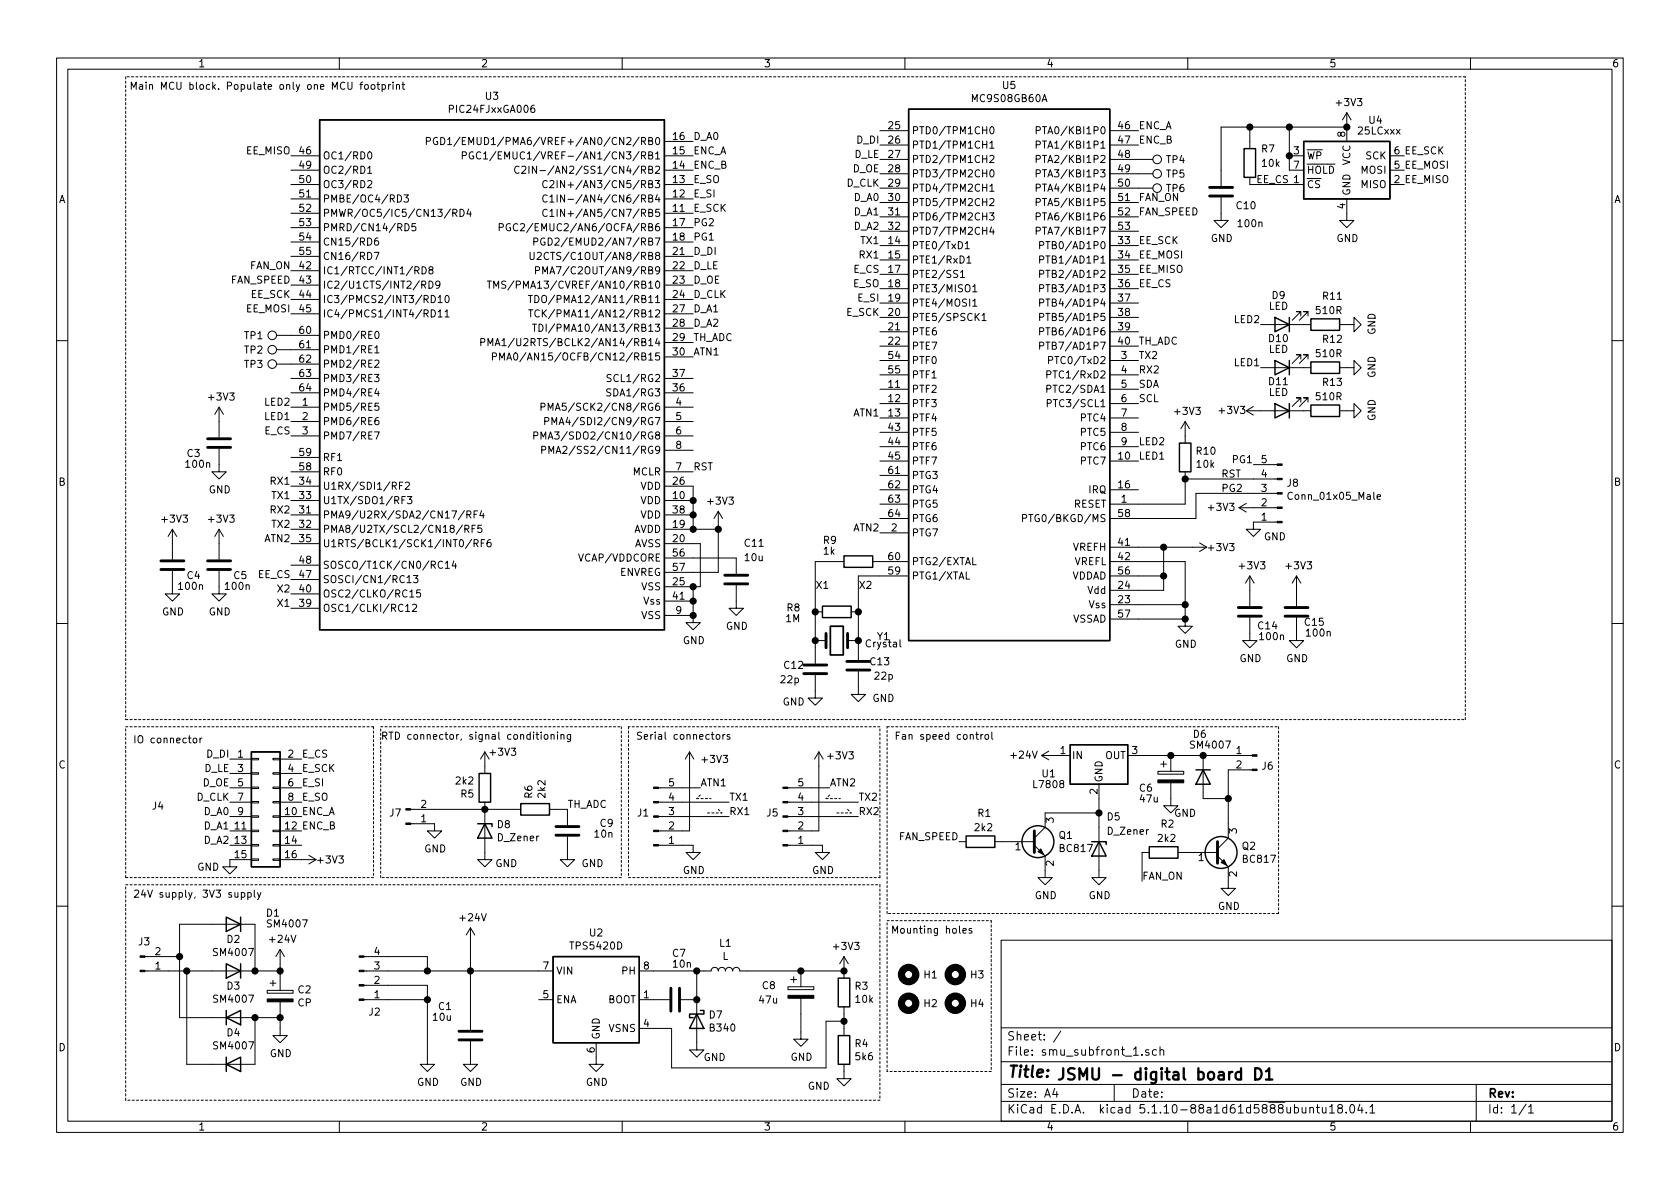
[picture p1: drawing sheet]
<svg xmlns="http://www.w3.org/2000/svg" width="297mm" height="210mm" viewBox="0 0 297 210" stroke-linecap="round" stroke-linejoin="round" font-family="sans-serif">
<defs><g id="words">
<g font-size="2.8">
<text x="178" y="190.5">Title:</text>
<text x="186.7" y="191">JSMU - digital board D1</text>
</g>
<g font-size="2.1">
<text x="178" y="184">Sheet: /</text>
<text x="178" y="186.7">File: smu_subfront_1.sch</text>
<text x="178" y="196.9">KiCad E.D.A. kicad 5.1.10-88a1d61d5888ubuntu18.04.1</text>
<text x="178" y="194.1">Size: A4</text>
<text x="200" y="194.1">Date:</text>
<text x="263" y="194.1">Rev:</text>
<text x="263" y="196.9">Id: 1/1</text>
</g>
<g font-size="1.8">
<text x="35" y="11.9">1</text>
<text x="85" y="11.9">2</text>
<text x="135" y="11.9">3</text>
<text x="185" y="11.9">4</text>
<text x="235" y="11.9">5</text>
<text x="285" y="11.9">6</text>
<text x="22.9" y="15.9">Main MCU block. Populate only one MCU footprint</text>
<text x="85.9" y="17.6">U3</text>
<text x="177.3" y="15.7">U5</text>
<text x="79.7" y="20">PIC24FJxxGA006</text>
<text x="157.1" y="22.9">25</text>
<text x="161.2" y="23.7">PTD0/TPM1CH0</text>
<text x="172.1" y="18.1">MC9S08GB60A</text>
<text x="184.5" y="23.7">PTA0/KBI1P0</text>
<text x="197.8" y="22.9">46</text>
<text x="201.3" y="22.9">ENC_A</text>
<text x="236.4" y="18.8">+3V3</text>
<text x="240.2" y="23.8">25LCxxx</text>
<text x="242.1" y="21.9">U4</text>
<text x="43.6" y="27.3">EE_MISO</text>
<text x="53" y="27.3">46</text>
<text x="53" y="29.8">49</text>
<text x="57" y="28.2">OC1/RD0</text>
<text x="81.7" y="25.6">PGD1/EMUD1/PMA6/VREF+/AN0/CN2/RB0</text>
<text x="87.6" y="28.2">PGC1/EMUC1/VREF-/AN1/CN3/RB1</text>
<text x="119" y="29.8">14</text>
<text x="119" y="27.3">15</text>
<text x="119" y="24.8">16</text>
<text x="122.6" y="29.8">ENC_B</text>
<text x="122.6" y="27.3">ENC_A</text>
<text x="122.6" y="24.8">D_A0</text>
<text x="151.1" y="27.9">D_LE</text>
<text x="151.5" y="25.4">D_DI</text>
<text x="157.1" y="25.4">26</text>
<text x="157.1" y="27.9">27</text>
<text x="161.2" y="26.3">PTD1/TPM1CH1</text>
<text x="161.2" y="28.8">PTD2/TPM1CH2</text>
<text x="184.5" y="26.3">PTA1/KBI1P1</text>
<text x="184.5" y="28.8">PTA2/KBI1P2</text>
<text x="197.8" y="25.4">47</text>
<text x="197.8" y="27.9">48</text>
<text x="201.3" y="25.4">ENC_B</text>
<text x="206.2" y="28.9">TP4</text>
<text x="223.1" y="27">R7</text>
<text x="223.2" y="29.5">10k</text>
<text x="228.8" y="27.3">3</text>
<text x="228.8" y="29.8">7</text>
<text x="231" y="28.2">WP</text>
<text x="237.9" y="24.2" transform="rotate(-90 237.9 24.2)">8</text>
<text x="238.8" y="29.3" transform="rotate(-90 238.8 29.3)">VCC</text>
<text x="241.5" y="28.2">SCK</text>
<text x="246.5" y="29.8">5 EE_MOSI</text>
<text x="246.5" y="27.3">6 EE_SCK</text>
<text x="10.4" y="35.9">A</text>
<text x="53" y="32.4">50</text>
<text x="53" y="34.9">51</text>
<text x="57" y="30.7">OC2/RD1</text>
<text x="57" y="33.3">OC3/RD2</text>
<text x="57" y="35.8">PMBE/OC4/RD3</text>
<text x="96.4" y="30.7">C2IN-/AN2/SS1/CN4/RB2</text>
<text x="99.8" y="33.3">C2IN+/AN3/CN5/RB3</text>
<text x="100.3" y="35.8">C1IN-/AN4/CN6/RB4</text>
<text x="119" y="34.9">12</text>
<text x="119" y="32.4">13</text>
<text x="122.6" y="32.4">E_SO</text>
<text x="122.6" y="34.9">E_SI</text>
<text x="149.7" y="33">D_CLK</text>
<text x="150.7" y="30.5">D_OE</text>
<text x="151.1" y="35.6">D_A0</text>
<text x="157.1" y="30.5">28</text>
<text x="157.1" y="33">29</text>
<text x="157.1" y="35.6">30</text>
<text x="161.2" y="31.4">PTD3/TPM2CH0</text>
<text x="161.2" y="33.9">PTD4/TPM2CH1</text>
<text x="184.5" y="31.4">PTA3/KBI1P3</text>
<text x="184.5" y="33.9">PTA4/KBI1P4</text>
<text x="197.8" y="30.5">49</text>
<text x="197.8" y="33">50</text>
<text x="197.8" y="35.6">51</text>
<text x="201.3" y="35.6">FAN_ON</text>
<text x="206.2" y="34">TP6</text>
<text x="206.2" y="31.4">TP5</text>
<text x="222.2" y="32.4">EE_CS 1</text>
<text x="231" y="33.3">CS</text>
<text x="231" y="30.7">HOLD</text>
<text x="238.8" y="34.7" transform="rotate(-90 238.8 34.7)">GND</text>
<text x="240.7" y="33.3">MISO</text>
<text x="240.7" y="30.7">MOSI</text>
<text x="246.5" y="32.4">2 EE_MISO</text>
<text x="285.4" y="35.9">A</text>
<text x="53" y="37.5">52</text>
<text x="53" y="40">53</text>
<text x="57" y="38.3">PMWR/OC5/IC5/CN13/RD4</text>
<text x="57" y="40.9">PMRD/CN14/RD5</text>
<text x="91.9" y="40.9">PGC2/EMUC2/AN6/OCFA/RB6</text>
<text x="99.8" y="38.3">C1IN+/AN5/CN7/RB5</text>
<text x="119" y="37.5">11</text>
<text x="119" y="40">17</text>
<text x="122.6" y="37.5">E_SCK</text>
<text x="122.6" y="40">PG2</text>
<text x="151.1" y="38.1">D_A1</text>
<text x="151.1" y="40.6">D_A2</text>
<text x="157.1" y="38.1">31</text>
<text x="157.1" y="40.6">32</text>
<text x="161.2" y="36.4">PTD5/TPM2CH2</text>
<text x="161.2" y="39">PTD6/TPM2CH3</text>
<text x="161.2" y="41.5">PTD7/TPM2CH4</text>
<text x="184.5" y="36.4">PTA5/KBI1P5</text>
<text x="184.5" y="39">PTA6/KBI1P6</text>
<text x="184.5" y="41.5">PTA7/KBI1P7</text>
<text x="197.8" y="38.1">52</text>
<text x="197.8" y="40.6">53</text>
<text x="201.3" y="38.1">FAN_SPEED</text>
<text x="218.7" y="37">C10</text>
<text x="219" y="40.2">100n</text>
<text x="237.9" y="36.9" transform="rotate(-90 237.9 36.9)">4</text>
<text x="44.2" y="47.6">FAN_ON</text>
<text x="53" y="47.6">42</text>
<text x="53" y="42.5">54</text>
<text x="53" y="45.1">55</text>
<text x="57" y="43.4">CN15/RD6</text>
<text x="57" y="46">CN16/RD7</text>
<text x="96.6" y="46">U2CTS/C1OUT/AN8/RB8</text>
<text x="97.4" y="43.4">PGD2/EMUD2/AN7/RB7</text>
<text x="119" y="42.5">18</text>
<text x="119" y="45.1">21</text>
<text x="119" y="47.6">22</text>
<text x="122.6" y="47.6">D_LE</text>
<text x="122.6" y="45.1">D_DI</text>
<text x="122.6" y="42.5">PG1</text>
<text x="152.1" y="45.7">RX1</text>
<text x="152.3" y="43.2">TX1</text>
<text x="157.1" y="43.2">14</text>
<text x="157.1" y="45.7">15</text>
<text x="161.2" y="44.1">PTE0/TxD1</text>
<text x="161.2" y="46.6">PTE1/RxD1</text>
<text x="185" y="44.1">PTB0/AD1P0</text>
<text x="185" y="46.6">PTB1/AD1P1</text>
<text x="197.8" y="43.2">33</text>
<text x="197.8" y="45.7">34</text>
<text x="201.3" y="43.2">EE_SCK</text>
<text x="201.3" y="45.7">EE_MOSI</text>
<text x="214.1" y="42.8">GND</text>
<text x="236.3" y="42.8">GND</text>
<text x="40.8" y="50.2">FAN_SPEED</text>
<text x="44.3" y="52.7">EE_SCK</text>
<text x="53" y="50.2">43</text>
<text x="53" y="52.7">44</text>
<text x="57" y="48.5">IC1/RTCC/INT1/RD8</text>
<text x="57" y="51">IC2/U1CTS/INT2/RD9</text>
<text x="57" y="53.6">IC3/PMCS2/INT3/RD10</text>
<text x="90.3" y="51">TMS/PMA13/CVREF/AN10/RB10</text>
<text x="96.8" y="53.6">TDO/PMA12/AN11/RB11</text>
<text x="97.5" y="48.5">PMA7/C2OUT/AN9/RB9</text>
<text x="119" y="50.2">23</text>
<text x="119" y="52.7">24</text>
<text x="122.6" y="52.7">D_CLK</text>
<text x="122.6" y="50.2">D_OE</text>
<text x="150.9" y="50.8">E_SO</text>
<text x="151" y="48.3">E_CS</text>
<text x="151.7" y="53.3">E_SI</text>
<text x="157.1" y="48.3">17</text>
<text x="157.1" y="50.8">18</text>
<text x="157.1" y="53.3">19</text>
<text x="161.2" y="49.1">PTE2/SS1</text>
<text x="161.2" y="51.7">PTE3/MISO1</text>
<text x="185" y="49.1">PTB2/AD1P2</text>
<text x="185" y="51.7">PTB3/AD1P3</text>
<text x="197.8" y="48.3">35</text>
<text x="197.8" y="50.8">36</text>
<text x="197.8" y="53.3">37</text>
<text x="201.3" y="48.3">EE_MISO</text>
<text x="201.3" y="50.8">EE_CS</text>
<text x="224.9" y="52.9">D9</text>
<text x="234" y="53">R11</text>
<text x="43.2" y="60">TP1</text>
<text x="43.6" y="55.2">EE_MOSI</text>
<text x="53" y="55.2">45</text>
<text x="53" y="59">60</text>
<text x="57" y="56.1">IC4/PMCS1/INT4/RD11</text>
<text x="57" y="59.9">PMD0/RE0</text>
<text x="96.9" y="56.1">TCK/PMA11/AN12/RB12</text>
<text x="97.7" y="58.7">TDI/PMA10/AN13/RB13</text>
<text x="119" y="55.2">27</text>
<text x="119" y="57.8">28</text>
<text x="122.6" y="57.8">D_A2</text>
<text x="122.6" y="55.2">D_A1</text>
<text x="149.7" y="55.9">E_SCK</text>
<text x="157.1" y="55.9">20</text>
<text x="157.1" y="58.4">21</text>
<text x="161.2" y="54.2">PTE4/MOSI1</text>
<text x="161.2" y="56.8">PTE5/SPSCK1</text>
<text x="161.2" y="59.3">PTE6</text>
<text x="185" y="54.2">PTB4/AD1P4</text>
<text x="185" y="56.8">PTB5/AD1P5</text>
<text x="185" y="59.3">PTB6/AD1P6</text>
<text x="197.8" y="55.9">38</text>
<text x="197.8" y="58.4">39</text>
<text x="218.4" y="57.1">LED2</text>
<text x="224.3" y="54.8">LED</text>
<text x="232.8" y="55.5">510R</text>
<text x="243.2" y="59.2" transform="rotate(-90 243.2 59.2)">GND</text>
<text x="43.2" y="62.5">TP2</text>
<text x="43.2" y="65.1">TP3</text>
<text x="53" y="61.6">61</text>
<text x="53" y="64.1">62</text>
<text x="57" y="62.5">PMD1/RE1</text>
<text x="57" y="65">PMD2/RE2</text>
<text x="89.4" y="61.2">PMA1/U2RTS/BCLK2/AN14/RB14</text>
<text x="91.5" y="63.7">PMA0/AN15/OCFB/CN12/RB15</text>
<text x="119" y="60.3">29</text>
<text x="119" y="62.9">30</text>
<text x="122.6" y="60.3">TH_ADC</text>
<text x="122.6" y="62.9">ATN1</text>
<text x="157.1" y="61">22</text>
<text x="157.1" y="63.5">54</text>
<text x="161.2" y="61.8">PTE7</text>
<text x="161.2" y="64.4">PTF0</text>
<text x="185" y="61.8">PTB7/AD1P7</text>
<text x="186.4" y="64.4">PTC0/TxD2</text>
<text x="197.8" y="61">40</text>
<text x="198.3" y="63.5">3</text>
<text x="201.3" y="63.5">TX2</text>
<text x="201.3" y="61">TH_ADC</text>
<text x="218.4" y="64.8">LED1</text>
<text x="224.3" y="62.4">LED</text>
<text x="224.4" y="60.5">D10</text>
<text x="232.8" y="63.2">510R</text>
<text x="234" y="60.6">R12</text>
<text x="37" y="70.8">+3V3</text>
<text x="46.9" y="71.7">LED2</text>
<text x="53" y="66.7">63</text>
<text x="53" y="69.2">64</text>
<text x="53.5" y="71.7">1</text>
<text x="57" y="67.6">PMD3/RE3</text>
<text x="57" y="70.1">PMD4/RE4</text>
<text x="108.1" y="70.1">SDA1/RG3</text>
<text x="108.3" y="67.6">SCL1/RG2</text>
<text x="119" y="69.2">36</text>
<text x="119" y="66.7">37</text>
<text x="119.5" y="71.7">4</text>
<text x="157.1" y="68.6">11</text>
<text x="157.1" y="71.1">12</text>
<text x="157.1" y="66">55</text>
<text x="161.2" y="69.5">PTF2</text>
<text x="161.2" y="66.9">PTF1</text>
<text x="186" y="69.5">PTC2/SDA1</text>
<text x="186.2" y="66.9">PTC1/RxD2</text>
<text x="198.3" y="66">4</text>
<text x="198.3" y="68.6">5</text>
<text x="198.3" y="71.1">6</text>
<text x="201.3" y="71.1">SCL</text>
<text x="201.3" y="68.6">SDA</text>
<text x="201.3" y="66">RX2</text>
<text x="224.3" y="70">LED</text>
<text x="224.4" y="68.1">D11</text>
<text x="232.8" y="70.8">510R</text>
<text x="234" y="68.2">R13</text>
<text x="243.2" y="66.8" transform="rotate(-90 243.2 66.8)">GND</text>
<text x="46.8" y="76.8">E_CS</text>
<text x="46.9" y="74.3">LED1</text>
<text x="53.5" y="74.3">2</text>
<text x="53.5" y="76.8">3</text>
<text x="57" y="72.6">PMD5/RE5</text>
<text x="57" y="75.2">PMD6/RE6</text>
<text x="57" y="77.7">PMD7/RE7</text>
<text x="97.6" y="77.7">PMA3/SDO2/CN10/RG8</text>
<text x="98.7" y="72.6">PMA5/SCK2/CN8/RG6</text>
<text x="99.5" y="75.2">PMA4/SDI2/CN9/RG7</text>
<text x="119.5" y="74.3">5</text>
<text x="119.5" y="76.8">6</text>
<text x="151" y="73.7">ATN1</text>
<text x="157.1" y="73.7">13</text>
<text x="157.1" y="76.2">43</text>
<text x="161.2" y="72">PTF3</text>
<text x="161.2" y="74.5">PTF4</text>
<text x="161.2" y="77.1">PTF5</text>
<text x="186.2" y="72">PTC3/SCL1</text>
<text x="191.2" y="74.5">PTC4</text>
<text x="191.2" y="77.1">PTC5</text>
<text x="198.3" y="73.7">7</text>
<text x="198.3" y="76.2">8</text>
<text x="207.8" y="73.4">+3V3</text>
<text x="215.7" y="73.2">+3V3</text>
<text x="243.2" y="74.5" transform="rotate(-90 243.2 74.5)">GND</text>
<text x="33" y="82.7">100n</text>
<text x="33.1" y="80.8">C3</text>
<text x="53" y="83.2">58</text>
<text x="53" y="80.6">59</text>
<text x="57" y="81.5">RF1</text>
<text x="99.1" y="80.3">PMA2/SS2/CN11/RG9</text>
<text x="119.5" y="83.2">7</text>
<text x="119.5" y="79.4">8</text>
<text x="122.6" y="83.2">RST</text>
<text x="157.1" y="78.7">44</text>
<text x="157.1" y="81.3">45</text>
<text x="157.1" y="83.8">61</text>
<text x="161.2" y="79.6">PTF6</text>
<text x="161.2" y="82.2">PTF7</text>
<text x="191.2" y="82.2">PTC7</text>
<text x="191.2" y="79.6">PTC6</text>
<text x="197.8" y="81.3">10</text>
<text x="198.3" y="78.7">9</text>
<text x="201.3" y="78.7">LED2</text>
<text x="201.3" y="81.3">LED1</text>
<text x="211.6" y="80.4">R10</text>
<text x="211.7" y="82.7">10k</text>
<text x="218.1" y="81.9">PG1</text>
<text x="223" y="81.9">5</text>
<text x="10.4" y="85.9">B</text>
<text x="36.9" y="87.2">GND</text>
<text x="48" y="85.7">RX1</text>
<text x="48.2" y="88.3">TX1</text>
<text x="53" y="88.3">33</text>
<text x="53" y="85.7">34</text>
<text x="57" y="89.1">U1TX/SDO1/RF3</text>
<text x="57" y="86.6">U1RX/SDI1/RF2</text>
<text x="57" y="84.1">RF0</text>
<text x="111.9" y="84.1">MCLR</text>
<text x="113.2" y="89.1">VDD</text>
<text x="113.2" y="86.6">VDD</text>
<text x="119" y="88.3">10</text>
<text x="119" y="85.7">26</text>
<text x="125.3" y="89.2">+3V3</text>
<text x="157.1" y="86.4">62</text>
<text x="157.1" y="88.9">63</text>
<text x="161.2" y="84.7">PTG3</text>
<text x="161.2" y="87.2">PTG4</text>
<text x="161.2" y="89.8">PTG5</text>
<text x="189.8" y="89.8">RESET</text>
<text x="192.6" y="87.2">IRQ</text>
<text x="197.8" y="86.4">16</text>
<text x="198.3" y="88.9">1</text>
<text x="215.9" y="84.4">RST</text>
<text x="215.9" y="87">PG2</text>
<text x="223" y="89.5">2</text>
<text x="223" y="87">3</text>
<text x="223" y="84.4">4</text>
<text x="227.6" y="86.1">J8</text>
<text x="228.2" y="88.4">Conn_01x05_Male</text>
<text x="285.4" y="85.9">B</text>
<text x="28.8" y="92.4">+3V3</text>
<text x="37" y="92.4">+3V3</text>
<text x="46.8" y="95.9">ATN2</text>
<text x="48" y="90.8">RX2</text>
<text x="48.2" y="93.3">TX2</text>
<text x="53" y="90.8">31</text>
<text x="53" y="93.3">32</text>
<text x="53" y="95.9">35</text>
<text x="57" y="91.7">PMA9/U2RX/SDA2/CN17/RF4</text>
<text x="57" y="94.2">PMA8/U2TX/SCL2/CN18/RF5</text>
<text x="112" y="94.2">AVDD</text>
<text x="113.2" y="91.7">VDD</text>
<text x="119" y="93.3">19</text>
<text x="119" y="95.9">20</text>
<text x="119" y="90.8">38</text>
<text x="151" y="94">ATN2</text>
<text x="157.1" y="91.4">64</text>
<text x="157.6" y="94">2</text>
<text x="161.2" y="94.9">PTG7</text>
<text x="161.2" y="92.3">PTG6</text>
<text x="182.2" y="92.3">PTG0/BKGD/MS</text>
<text x="197.8" y="91.4">58</text>
<text x="213.8" y="90.3">+3V3</text>
<text x="223" y="92.1">1</text>
<text x="223.5" y="95.5">GND</text>
<text x="53" y="99.7">48</text>
<text x="57" y="96.8">U1RTS/BCLK1/SCK1/INT0/RF6</text>
<text x="57" y="100.6">SOSCO/T1CK/CN0/RC14</text>
<text x="102.7" y="99.3">VCAP/VDDCORE</text>
<text x="109.5" y="101.8">ENVREG</text>
<text x="112.1" y="96.8">AVSS</text>
<text x="119" y="98.4">56</text>
<text x="119" y="101">57</text>
<text x="131.7" y="96.7">C11</text>
<text x="131.8" y="99.2">10u</text>
<text x="145.6" y="96.2">R9</text>
<text x="145.6" y="98.1">1k</text>
<text x="157.1" y="101.6">59</text>
<text x="157.1" y="99.1">60</text>
<text x="161.2" y="99.9">PTG2/EXTAL</text>
<text x="189.7" y="97.4">VREFH</text>
<text x="189.9" y="99.9">VREFL</text>
<text x="197.8" y="96.5">41</text>
<text x="197.8" y="99.1">42</text>
<text x="197.8" y="101.6">56</text>
<text x="213.8" y="97.5">+3V3</text>
<text x="219.3" y="100.7">+3V3</text>
<text x="227.5" y="100.7">+3V3</text>
<text x="31.7" y="104.3">100n</text>
<text x="33.1" y="102.4">C4</text>
<text x="40" y="104.3">100n</text>
<text x="41.4" y="102.4">C5</text>
<text x="45.6" y="102.2">EE_CS</text>
<text x="49.3" y="107.3">X1</text>
<text x="49.3" y="104.8">X2</text>
<text x="53" y="107.3">39</text>
<text x="53" y="104.8">40</text>
<text x="53" y="102.2">47</text>
<text x="57" y="105.7">OSC2/CLKO/RC15</text>
<text x="57" y="103.1">SOSCI/CN1/RC13</text>
<text x="113.4" y="104.4">VSS</text>
<text x="113.8" y="106.9">Vss</text>
<text x="119" y="103.5">25</text>
<text x="119" y="106">41</text>
<text x="144.1" y="104.1">X1</text>
<text x="151.8" y="104.1">X2</text>
<text x="161.2" y="102.5">PTG1/XTAL</text>
<text x="189.4" y="102.5">VDDAD</text>
<text x="192.4" y="105">Vdd</text>
<text x="192.6" y="107.6">Vss</text>
<text x="197.8" y="106.7">23</text>
<text x="197.8" y="104.1">24</text>
<text x="28.7" y="108.8">GND</text>
<text x="36.9" y="108.8">GND</text>
<text x="57" y="108.2">OSC1/CLKI/RC12</text>
<text x="113.4" y="109.5">VSS</text>
<text x="119.5" y="108.6">9</text>
<text x="120.7" y="113.9">GND</text>
<text x="128.3" y="111.4">GND</text>
<text x="139" y="110">1M</text>
<text x="139.2" y="108.1">R8</text>
<text x="155.1" y="113.2">Y1</text>
<text x="189.6" y="110.1">VSSAD</text>
<text x="197.8" y="109.2">57</text>
<text x="222.5" y="111.3">C14</text>
<text x="222.9" y="113.2">100n</text>
<text x="230.8" y="110.7">C15</text>
<text x="231.1" y="112.6">100n</text>
<text x="138.7" y="118.3">C12</text>
<text x="153.2" y="114.5">Crystal</text>
<text x="153.9" y="117.6">C13</text>
<text x="207.7" y="114.5">GND</text>
<text x="219.2" y="117.1">GND</text>
<text x="227.4" y="117.1">GND</text>
<text x="138.1" y="120.8">22p</text>
<text x="138.4" y="124.8">GND</text>
<text x="154.3" y="124.1">GND</text>
<text x="154.7" y="120.2">22p</text>
<text x="23.5" y="131.4">IO connector</text>
<text x="67.3" y="130.8">RTD connector, signal conditioning</text>
<text x="112.4" y="130.8">Serial connectors</text>
<text x="158.1" y="130.8">Fan speed control</text>
<text x="211" y="130.5">D6</text>
<text x="10.4" y="135.9">C</text>
<text x="36.1" y="136.5">D_LE</text>
<text x="36.6" y="134">D_DI</text>
<text x="42.1" y="134">1</text>
<text x="42.1" y="136.5">3</text>
<text x="51" y="134">2</text>
<text x="51" y="136.5">4</text>
<text x="53.3" y="134">E_CS</text>
<text x="53.3" y="136.5">E_SCK</text>
<text x="86.8" y="133.6">+3V3</text>
<text x="124.3" y="134.9">+3V3</text>
<text x="146.5" y="134.3">+3V3</text>
<text x="178.9" y="134.2">+24V</text>
<text x="184.3" y="137.5">U1</text>
<text x="187.5" y="133.3">1</text>
<text x="189.5" y="134.2">IN</text>
<text x="195.4" y="134.2">OUT</text>
<text x="200.2" y="133.3">3</text>
<text x="210.7" y="132.4">SM4007</text>
<text x="218.6" y="133.3">1</text>
<text x="218.6" y="135.9">2</text>
<text x="223.2" y="136.1">J6</text>
<text x="285.4" y="135.9">C</text>
<text x="27" y="143.2">J4</text>
<text x="34.7" y="141.6">D_CLK</text>
<text x="35.8" y="139.1">D_OE</text>
<text x="42.1" y="139.1">5</text>
<text x="42.1" y="141.6">7</text>
<text x="51" y="139.1">6</text>
<text x="51" y="141.6">8</text>
<text x="53.3" y="139.1">E_SI</text>
<text x="53.3" y="141.6">E_SO</text>
<text x="74.4" y="142.9">2</text>
<text x="80.7" y="138.7">2k2</text>
<text x="81.5" y="141">R5</text>
<text x="94.1" y="141.1" transform="rotate(-90 94.1 141.1)">R6</text>
<text x="96.4" y="141" transform="rotate(-90 96.4 141)">2k2</text>
<text x="100.3" y="142.9">TH_ADC</text>
<text x="118.3" y="141.6">4</text>
<text x="118.3" y="139.1">5</text>
<text x="123.8" y="139.1">ATN1</text>
<text x="128.9" y="141.6">TX1</text>
<text x="141.1" y="141.6">4</text>
<text x="141.1" y="139.1">5</text>
<text x="146.7" y="139.1">ATN2</text>
<text x="151.8" y="141.6">TX2</text>
<text x="182.9" y="139.4">L7808</text>
<text x="194.1" y="140.4" transform="rotate(-90 194.1 140.4)">2</text>
<text x="194.9" y="138.4" transform="rotate(-90 194.9 138.4)">GND</text>
<text x="201.5" y="140">C6</text>
<text x="201.6" y="141.9">47u</text>
<text x="36.1" y="144.1">D_A0</text>
<text x="36.1" y="146.7">D_A1</text>
<text x="36.1" y="149.2">D_A2</text>
<text x="41.6" y="146.7">11</text>
<text x="41.6" y="149.2">13</text>
<text x="42.1" y="144.1">9</text>
<text x="50.5" y="144.1">10 ENC_A</text>
<text x="50.5" y="146.7">12 ENC_B</text>
<text x="50.5" y="149.2">14</text>
<text x="68.9" y="144.4">J7</text>
<text x="74.4" y="145.4">1</text>
<text x="88" y="146.5">D8</text>
<text x="88.1" y="148.8">D_Zener</text>
<text x="105.2" y="148.1">10n</text>
<text x="106.1" y="146.2">C9</text>
<text x="112.8" y="144.4">J1</text>
<text x="118.3" y="149.2">1</text>
<text x="118.3" y="146.7">2</text>
<text x="118.3" y="144.1">3</text>
<text x="128.9" y="144.1">RX1</text>
<text x="135.6" y="144.4">J5</text>
<text x="141.1" y="149.2">1</text>
<text x="141.1" y="146.7">2</text>
<text x="141.1" y="144.1">3</text>
<text x="151.8" y="144.1">RX2</text>
<text x="158.9" y="148.6">FAN_SPEED</text>
<text x="172.4" y="147">2k2</text>
<text x="172.9" y="144.4">R1</text>
<text x="186.3" y="145.5" transform="rotate(-90 186.3 145.5)">3</text>
<text x="187.3" y="148.4">Q1</text>
<text x="195.8" y="145.1">D5</text>
<text x="195.9" y="147.6">D_Zener</text>
<text x="204.8" y="148.9">2k2</text>
<text x="205.3" y="146.3">R2</text>
<text x="207.6" y="144.4">GND</text>
<text x="218.7" y="147.4" transform="rotate(-90 218.7 147.4)">3</text>
<text x="34.9" y="154">GND</text>
<text x="41.6" y="151.8">15</text>
<text x="50.5" y="151.8">16</text>
<text x="56.3" y="152.7">+3V3</text>
<text x="75" y="150.7">GND</text>
<text x="87.6" y="153.3">GND</text>
<text x="102.8" y="153.3">GND</text>
<text x="120.7" y="154.6">GND</text>
<text x="143.6" y="154.6">GND</text>
<text x="179.5" y="150.4">1</text>
<text x="186.3" y="153.1" transform="rotate(-90 186.3 153.1)">2</text>
<text x="187.5" y="150.7">BC817</text>
<text x="201.9" y="155.6">FAN_ON</text>
<text x="211.9" y="152.3">1</text>
<text x="218.7" y="155" transform="rotate(-90 218.7 155)">2</text>
<text x="219.7" y="150.3">Q2</text>
<text x="219.9" y="152.6">BC817</text>
<text x="23.5" y="158.7">24V supply, 3V3 supply</text>
<text x="183" y="159">GND</text>
<text x="192.5" y="159">GND</text>
<text x="215.3" y="160.9">GND</text>
<text x="24.5" y="167.2">J3</text>
<text x="40.2" y="166.7">D2</text>
<text x="47.1" y="162.1">D1</text>
<text x="47.5" y="164">SM4007</text>
<text x="47.8" y="166.7">+24V</text>
<text x="81.5" y="162.9">+24V</text>
<text x="101.1" y="167.9">TPS5420D</text>
<text x="104.3" y="165.6">U2</text>
<text x="127.3" y="167.4">L1</text>
<text x="147.5" y="168">+3V3</text>
<text x="157.5" y="165.1">Mounting holes</text>
<text x="27.5" y="171.4">1</text>
<text x="27.5" y="168.9">2</text>
<text x="38" y="169.1">SM4007</text>
<text x="66.2" y="174">2</text>
<text x="66.2" y="171.4">3</text>
<text x="66.2" y="168.9">4</text>
<text x="96" y="171.4">7</text>
<text x="98.3" y="172.3">VIN</text>
<text x="110.1" y="172.3">PH</text>
<text x="113.8" y="171.4">8</text>
<text x="118.9" y="169.2">C7</text>
<text x="119.1" y="171.1">10n</text>
<text x="127.7" y="169.7">L</text>
<text x="163.4" y="173">H1</text>
<text x="171.7" y="173">H3</text>
<text x="38" y="177.3">SM4007</text>
<text x="40.2" y="175">D3</text>
<text x="52.7" y="178">CP</text>
<text x="52.7" y="175.7">C2</text>
<text x="65.3" y="179.6">J2</text>
<text x="66.2" y="176.5">1</text>
<text x="77.6" y="178.6">C1</text>
<text x="96" y="176.5">5</text>
<text x="98.3" y="177.4">ENA</text>
<text x="107.4" y="177.4">BOOT</text>
<text x="113.8" y="176.5">1</text>
<text x="134.3" y="177.5">47u</text>
<text x="134.8" y="174.9">C8</text>
<text x="151.2" y="175">R3</text>
<text x="151.3" y="177.3">10k</text>
<text x="163.4" y="178.1">H2</text>
<text x="171.7" y="178.1">H4</text>
<text x="10.4" y="185.9">D</text>
<text x="38" y="185.6">SM4007</text>
<text x="40.2" y="183.3">D4</text>
<text x="76.6" y="180.5">10u</text>
<text x="106" y="183.9" transform="rotate(-90 106 183.9)">GND</text>
<text x="107.7" y="182.5">VSNS</text>
<text x="113.8" y="181.6">4</text>
<text x="125.4" y="180.1">D7</text>
<text x="125.6" y="182.4">B340</text>
<text x="151.2" y="185.2">R4</text>
<text x="285.4" y="185.9">D</text>
<text x="47.7" y="186.9">GND</text>
<text x="105.2" y="186.2" transform="rotate(-90 105.2 186.2)">6</text>
<text x="124.4" y="187.6">GND</text>
<text x="139.8" y="187.6">GND</text>
<text x="151.3" y="187.5">5k6</text>
<text x="73.7" y="192">GND</text>
<text x="81.4" y="192">GND</text>
<text x="103.6" y="192">GND</text>
<text x="142.8" y="192.7">GND</text>
<text x="35" y="199.9">1</text>
<text x="85" y="199.9">2</text>
<text x="135" y="199.9">3</text>
<text x="185" y="199.9">4</text>
<text x="235" y="199.9">5</text>
<text x="285" y="199.9">6</text>
</g>
</g></defs>
<g fill="none" stroke="#000" stroke-width=".18">
<path d="M10 10.3h277v189.9h-277zM12 12.2h273v186.1h-273zM60 10.3v1.9M63.6 15h.5M64.1 14.5l-.3 .2v1.1M64.6 15h.3l.2 .1-.1 .6-.3 .1-.2-.2zM65.7 15h.3l.3 .2-.1 .5-.3 .1-.3-.2zM66.6 15h.5M66.8 14.5v1.1l.3 .2M67.6 15h.3l.2 .2-.1 .5h-.4M67.6 15v1.2M68.7 15v.8"/>
<path d="M69.1 15l-.4 .2M69.5 14.5v.2M69.5 15v.8M70.1 15.1l.2-.1h.3v.8M70.1 15v.8M71.1 15h.5M71.2 14.5v1.1l.4 .2M94.5 18.6l-.4 .1a.87 .87 0 0 0 0 1.2l.4-.1v-.6l-.4-.1-.2 .2M110 10.3v1.9M160 10.3v1.9M210 10.3v1.9M238.1 19.9v5.1"/>
<path d="M238.1 19.9l-.7 1.3M238.1 19.9l.8 1.3M260 10.3v1.9M51.4 32.6h5.1M51.4 27.6h5.1M51.4 30.1h5.1M51.4 37.7h5.1M51.4 35.2h5.1M65 29.7l.4-.3v1.3M65 32l.5-.1 .2 .1v.3v.2l-.8 .7h.8M65 30.7h.7M65.1 27l.2-.2a.67 .67 0 0 1 .5 .7 .67 .67 0 0 1-.5 .6l-.3-.5z"/>
<path d="M70.3 34.5a.64 .64 0 0 1 .7 .6 .64 .64 0 0 1-.7 .6zM71.4 34.5h.8l-.4 .4 .3 .2 .1 .4-.2 .2-.6-.1M71.6 39.5a.64 .64 0 0 1 .7 .7 .64 .64 0 0 1-.7 .6zM73.5 39.5h-.6l-.1 .7 .2-.2 .5 .2v.5l-.2 .1-.5-.1M75.4 25l.6-.1 .1-.2-.1-.3-.1-.1h-.5v1.3M77.3 24.4a.59 .59 0 0 0-.7 .5 .59 .59 0 0 0 .7 .6l.1-.5h-.3M77.9 24.3a.64 .64 0 0 1 .8 .6 .64 .64 0 0 1-.8 .7zM79.1 24.7l.4-.4v1.3M79.1 25.6h.8M79.7 37l-1.1 1.6M80.1 37.7l.6-.1 .1-.2-.1-.3-.2-.1h-.4v1.3M80.4 37.7l.4 .6"/>
<path d="M81.3 37a.64 .64 0 0 1 .8 .6 .64 .64 0 0 1-.8 .7zM81.3 24.3l-1.1 1.6M81.7 27.5h.6l.2-.2-.1-.3-.2-.2h-.5v1.3M82.9 37l-.4 .8h.8M83.2 37.4v.9M83.7 26.9a.59 .59 0 0 0-.8 .6 .59 .59 0 0 0 .8 .6v-.5h-.2M85 27a.6 .6 0 0 0-.8 .4 .6 .6 0 0 0 .6 .7l.2-.1M85.5 27.2l.4-.4v1.3M85.5 28.1h.7M87.7 26.8l-1.1 1.6M90.2 39.6a.59 .59 0 0 0-.7 .6 .59 .59 0 0 0 .7 .6l.1-.5h-.3M91.5 39.7a.6 .6 0 0 0-.8 .4 .6 .6 0 0 0 .6 .7l.2-.1"/>
<path d="M91.8 29.5a.6 .6 0 0 0-.9 .4 .6 .6 0 0 0 .6 .8l.3-.2M92.3 29.5l.5-.1 .2 .3-.1 .2-.7 .8h.8M93.5 29.4v1.3M94.9 29.4v1.3l-.8-1.3v1.3M95.5 30.2h.9M96.7 37.1a.51 .51 0 0 0-.6 0 .51 .51 0 0 0-.1 .6 .46 .46 0 0 0 .2 .5 .46 .46 0 0 0 .5-.1M96.7 34.6a.51 .51 0 0 0-.6 0 .51 .51 0 0 0-.1 .6 .46 .46 0 0 0 .2 .5 .46 .46 0 0 0 .5-.1M96.7 32a.51 .51 0 0 0-.6 0 .51 .51 0 0 0-.1 .7 .46 .46 0 0 0 .2 .5 .46 .46 0 0 0 .5-.1M97.2 37.4l.4-.4v1.3M97.2 34.8l.4-.3v1.2M97.2 32l.5-.1 .2 .4v.2l-.7 .7h.7M97.2 38.3h.7"/>
<path d="M97.2 35.7h.7M98.5 31.9v1.3M98.5 34.5v1.2M98.5 37v1.3M99.8 37v1.3l-.7-1.3v1.3M99.8 34.5v1.2l-.7-1.2v1.2M99.8 31.9v1.3l-.7-1.3v1.3M117.5 32.6h5.1M117.5 27.6h5.1M117.5 30.1h5.1M117.5 37.7h5.1M117.5 35.2h5.1"/>
<path d="M117.5 25h5.1M155.6 33.3h5.1M155.6 30.7h5.1M155.6 28.2h5.1M155.6 23.1h5.1M155.6 25.6h5.1M155.6 35.8h5.1M155.6 38.3h5.1M175 37.6h.7l-.4 .5 .4 .1v.6l-.2 .1-.5-.1M175 25.3l.4-.4v1.3M175 27.6l.5-.1 .2 .1v.2v.2l-.7 .7h.7M175 32.9l.4-.3v1.2"/>
<path d="M175 35.2l.5-.1 .2 .1v.3v.2l-.7 .7h.7M175 26.2h.7M175 33.8h.7M175.1 22.5l.2-.1a.67 .67 0 0 1 .5 .6 .67 .67 0 0 1-.5 .7l-.3-.5zM175.1 30.1l.2-.1a.67 .67 0 0 1 .5 .7 .67 .67 0 0 1-.5 .6l-.3-.5zM183.2 23.1l.7-.1v-.5l-.7-.1v1.3M183.2 25.6l.7-.1v-.4l-.7-.2v1.3M183.2 28.1l.7-.1v-.4l-.7-.1v1.2M183.2 30.7l.7-.1v-.5l-.7-.1v1.3M183.2 33.2l.7-.1v-.4l-.7-.1v1.2M183.2 35.8l.7-.1v-.5l-.7-.1v1.3M183.2 38.3l.7-.1v-.4l-.7-.2v1.3"/>
<path d="M196.2 33.3h7.6M196.2 30.7h7.6M196.2 28.2h7.6M196.2 23.1h5.1M196.2 25.6h5.1M196.2 35.8h5.1M196.2 38.3h5.1M215.9 34.9v4.1h1.3l-1.3 1.3-1.3-1.3h1.3M221 22.5v3.8M221 31.4v1.2h9.5M228 27.6h2.5M228 22.5v7.6h2.5"/>
<path d="M238.1 35.2v3.8h1.3l-1.3 1.3-1.2-1.3h1.2M238.1 22.5h-22.2v10.4M245.7 32.6h2.6M245.7 27.6h2.6M245.7 30.1h2.6M48.9 59.3h7.6M51.4 40.3h5.1M51.4 42.8h5.1M51.4 45.3h5.1M51.4 47.9h5.1M51.4 50.4h5.1M51.4 53h5.1"/>
<path d="M51.4 55.5h5.1M66.2 44.6h.8l-.5 1.3M66.4 58.7l.2-.1a.67 .67 0 0 1 .4 .6 .67 .67 0 0 1-.4 .7l-.3-.5zM66.8 42.1l-.4 .1-.2 .4 .1 .6 .2 .2 .3-.1 .2-.2-.2-.5h-.3l-.3 .2M73.4 47.8h.6l.1-.2-.1-.3-.2-.1h-.4v1.2M73.7 47.8l.4 .6M74.6 50.4l.6-.1v-.5l-.1-.1h-.5v1.3M74.6 47.2a.64 .64 0 0 1 .8 .6 .64 .64 0 0 1-.8 .6zM74.9 50.4l.4 .6M75.8 49.7a.64 .64 0 0 1 .8 .6 .64 .64 0 0 1-.8 .7zM76.1 47.7l-.2-.1v-.3l.4-.1 .2 .1v.3l-.6 .2-.1 .1v.3l.3 .2h.2l.3-.2-.1-.4-.2-.1M76.3 52.2a.64 .64 0 0 1 .7 .7 .64 .64 0 0 1-.7 .6z"/>
<path d="M76.3 54.8a.64 .64 0 0 1 .7 .6 .64 .64 0 0 1-.7 .7zM77.5 52.6l.3-.4v1.3M77.5 55.1l.3-.3v1.3M77.5 53.5h.7M77.5 56.1h.7M77.8 50.3l-.3 .2-.3-.1-.2-.1 .2-.5 .3-.1 .2 .1a.87 .87 0 0 1-.3 1.2h-.2M78.7 55.1l.3-.3v1.3M78.7 56.1h.7M78.8 52.4l.2-.2a.67 .67 0 0 1 .4 .7 .67 .67 0 0 1-.4 .6l-.2-.1-.1-.4zM86.2 49.7h.7M86.5 49.7v1.3M87.3 51v-1.3l.4 .9 .5-.9v1.3"/>
<path d="M88.3 40.2l.7-.1v-.4l-.7-.2v1.3M89.4 49.8l-.4-.1-.3 .1v.4l.6 .2 .1 .3-.2 .3-.5-.1M93.4 52.2h.7M93.5 54.8h.7M93.7 44.6v1.1l.3 .2h.2l.2-.2v-1.1M93.8 52.2v1.3M93.8 54.8v1.3M94.1 57.3h.8M94.4 42.7h.6v-.5l-.1-.1h-.5v1.3M94.5 57.3v1.3M94.6 52.2a.64 .64 0 0 1 .7 .7 .64 .64 0 0 1-.7 .6zM94.7 47.8h.6l.1-.5-.2-.1h-.5v1.2"/>
<path d="M95 44.7l.5-.1 .2 .4v.2l-.8 .7h.8M95.3 57.3a.64 .64 0 0 1 .7 .7 .64 .64 0 0 1-.7 .6zM95.4 54.9a.6 .6 0 0 0-.9 .4 .6 .6 0 0 0 .6 .8l.3-.2M95.8 52.4l.2-.1a.42 .42 0 0 1 .6 .1 .88 .88 0 0 1-.3 1.1h-.3a1.07 1.07 0 0 1-.2-1.1zM95.9 54.8v1.3M96 48.4v-1.2l.4 .9 .4-.9v1.2M96.1 55.3l.5 .8M96.3 42.2a.59 .59 0 0 0-.7 .5 .59 .59 0 0 0 .7 .6l.1-.5h-.3M96.6 57.3v1.3M96.6 54.8l-.7 .7M96.9 42.1a.64 .64 0 0 1 .7 .6 .64 .64 0 0 1-.7 .7zM98.1 57.3l-1.1 1.6"/>
<path d="M117.5 40.3h5.1M117.5 42.8h5.1M117.5 45.3h5.1M117.5 47.9h5.1M117.5 50.4h5.1M117.5 53h5.1M117.5 55.5h5.1M117.5 58h5.1M155.6 43.4h5.1M155.6 46h5.1M155.6 48.5h5.1M155.6 51h5.1"/>
<path d="M155.6 53.6h5.1M155.6 56.1h5.1M155.6 58.7h5.1M155.6 40.9h5.1M169.8 48.2l.4-.4v1.3M169.8 49.1h.7M170.7 43.1l.3-.4v1.3M170.7 44h.7M171 45.6l.3-.3v1.2M171 46.5h.7M172 50.7l.4-.4v1.3M172 53.2l.4-.3v1.2"/>
<path d="M172 51.6h.7M172 54.1h.7M173.6 55.8l.4-.4v1.3M173.6 56.7h.7M175.3 40.1l-.3 .9h.8M175.6 40.6v.8M183.2 40.8l.7-.1v-.4l-.7-.1v1.2M183.8 43.4l.6-.1 .2-.2-.1-.3-.2-.1h-.5v1.3M183.8 45.9h.6l.2-.2-.1-.3-.2-.1h-.5v1.2M183.8 48.5l.6-.1 .2-.2-.1-.3-.2-.1h-.5v1.3M183.8 51l.6-.1 .2-.1-.1-.3-.2-.2h-.5v1.3M183.8 53.5h.6l.2-.2-.1-.3-.2-.1h-.5v1.2"/>
<path d="M183.8 56.1l.6-.1 .2-.2-.1-.3-.2-.1h-.5v1.3M183.8 58.6h.6l.2-.2-.1-.3-.2-.1h-.5v1.2M196.2 43.4h5.1M196.2 46h5.1M196.2 48.5h5.1M196.2 51h5.1M196.2 53.6h5.1M196.2 56.1h5.1M196.2 58.7h5.1M196.2 40.9h5.1M222.9 57.4h8.9M230 55.9v-.8h-.8h.8l-1.5 1.5"/>
<path d="M231.3 55.9v-.8h-.8h.8l-1.6 1.5M236.9 57.4h2.5v-1.3l1.3 1.3-1.3 1.3v-1.3M10 60.2h2M38.7 79.4v4h1.3l-1.3 1.3-1.2-1.3h1.2M38.7 72v5.3M38.7 72l-.7 1.3M38.7 72l.8 1.3M48.9 61.8h7.6M48.9 64.4h7.6M51.4 72h5.1M51.4 74.5h5.1M51.4 77.1h5.1"/>
<path d="M51.4 69.5h5.1M51.4 66.9h5.1M66.2 76.4h.9l-.6 1.2M66.2 66.2h.8l-.4 .5 .4 .1v.6l-.2 .1-.6-.1M66.3 61.5l.3-.4v1.3M66.3 63.8l.5-.1 .2 .1v.2v.2l-.8 .7h.8M66.3 62.4h.7M66.6 68.7l-.3 .9h.8M66.9 73.8h-.3a.79 .79 0 0 0-.1 1.3l.5-.1v-.6l-.5-.1-.2 .3M66.9 69.2v.8M67 71.3h-.7v.6l.2-.1 .5 .1v.5l-.2 .2-.5-.2M85 60.5h.6l.1-.5-.2-.1h-.5v1.2"/>
<path d="M86.3 61.1v-1.2l.4 .9 .4-.9v1.2M87.1 63.1l.6-.1v-.5l-.1-.1h-.5v1.3M87.6 61.1l.4-1.2 .4 1.2M87.7 60.8h.6M88.3 63.7v-1.3l.4 .9 .5-.9v1.3M88.7 60.2l.4-.3v1.2M88.7 61.1h.8M89.6 63.7l.4-1.3 .4 1.3M89.7 63.3h.6M91 62.5l.1-.1a.67 .67 0 0 1 .5 .6 .67 .67 0 0 1-.5 .7 .83 .83 0 0 1-.1-1.2zM94.4 77h.6v-.5l-.1-.1h-.5v1.2M95.7 72l.6-.1v-.5l-.2-.1h-.4v1.3"/>
<path d="M95.7 77.6v-1.2l.4 .9 .4-.9v1.2M95.8 79.6l.6-.1v-.5l-.1-.1h-.5v1.3M96.3 74.5l.6-.1 .2-.1-.1-.3-.2-.2h-.5v1.3M96.9 72.6v-1.3l.4 .9 .5-.9v1.3M96.9 77.6l.4-1.2 .5 1.2M97.1 77.3h.5M97.6 75.1v-1.3l.4 .9 .4-.9v1.3M98.2 72.6l.4-1.3 .4 1.3M98.4 79.8h.6M98.9 75.1l.4-1.3 .4 1.3M99 74.7h.6M108 68.8h-.5l-.2 .1v.3l.6 .3 .1 .3-.3 .2h-.4"/>
<path d="M108.1 66.3l-.5-.1-.3 .3 .1 .3 .6 .2v.4l-.2 .1-.5-.1M117.5 72h5.1M117.5 74.5h5.1M117.5 60.6h5.1M117.5 77.1h5.1M117.5 63.1h5.1M117.5 69.5h5.1M117.5 66.9h5.1M117.5 79.6h5.1M155.6 68.8h5.1M155.6 71.4h5.1M155.6 73.9h5.1"/>
<path d="M155.6 61.2h5.1M155.6 63.7h5.1M155.6 66.3h5.1M155.6 76.4h5.1M155.6 79h5.1M183.8 61.2l.6-.1 .2-.2-.1-.3-.2-.1h-.5v1.3M185.1 66.2h.6l.1-.2v-.3l-.2-.1h-.5v1.2M185.1 68.8l.6-.1 .1-.2v-.3l-.2-.1h-.5v1.3M185.2 71.3l.6-.1v-.4l-.2-.1h-.4v1.2M185.4 63.7l.6-.1 .1-.1v-.3l-.2-.2h-.5v1.3M196.2 68.8h5.1M196.2 71.4h5.1"/>
<path d="M196.2 73.9h5.1M196.2 61.2h5.1M196.2 63.7h5.1M196.2 66.3h5.1M196.2 76.4h5.1M196.2 79h5.1M209.5 74.5v3.9M209.5 74.5l-.7 1.3M209.5 74.5l.8 1.3M220.3 72.6l1.3 .8M220.3 72.6h11.5M221.6 71.9l-1.3 .7"/>
<path d="M222.9 65h8.9M230 63.5v-.8h-.8h.8l-1.5 1.6M230 71.1v-.7h-.8h.8l-1.5 1.5M231.3 63.5v-.8h-.8h.8l-1.6 1.6M231.3 71.1v-.7h-.8h.8l-1.6 1.5M236.9 72.6h2.5v-1.2l1.3 1.2-1.3 1.3v-1.3M236.9 65h2.5v-1.3l1.3 1.3-1.3 1.3v-1.3M285 60.2h2M30.5 93.6v5.3M30.5 93.6l-.8 1.3M30.5 93.6l.7 1.3M38.7 93.6l-.7 1.3"/>
<path d="M38.7 93.6v5.3M38.7 93.6l.8 1.3M51.4 88.5h5.1M51.4 93.6h5.1M51.4 96.1h5.1M51.4 86h5.1M51.4 91.1h5.1M51.4 99.9h5.1M51.4 83.4h5.1M51.4 80.9h5.1M70.6 85.9h.5M71.1 88.4h.4"/>
<path d="M71.2 85.3h-.6v1.2M71.7 87.8h-.6v1.3M71.7 85.4l.4-.1 .2 .1 .1 .2-.1 .2-.7 .7h.8M72 87.8h.8l-.4 .5 .3 .1 .1 .4-.2 .3-.6-.2M78.3 99.4a.6 .6 0 0 0-.9 .4 .6 .6 0 0 0 .6 .7l.3-.1M78.7 99.6l.4-.4v1.3M80.2 99.2l-.2 .9h.7M80.5 99.7v.8M81.8 92.8l-1.1 1.7M82.1 90.3l-1.1 1.6M82.2 93.5l.7-.1v-.4l-.2-.1h-.5v1.3M82.5 93.5l.4 .7"/>
<path d="M82.5 91h.7v-.5l-.2-.2h-.5v1.3M82.9 91l.4 .6M83.4 95.4l-1.1 1.6M83.5 93.5h.4M83.8 96.1l.6-.1 .1-.5-.2-.1h-.5v1.3M83.8 91h.5M84 92.9h-.5v1.3M84.1 96.1l.4 .6M84.4 90.3h-.6v1.3M85.1 96h.4M85.1 90.3l-.3 .9h.8M85.1 92.9h-.6v.6l.5-.1 .2 .2v.3l-.2 .3-.5-.2"/>
<path d="M85.4 90.8v.8M85.7 95.4h-.6v1.3M86.7 95.4h-.2a.79 .79 0 0 0-.1 1.3l.4-.1v-.6l-.4-.1-.3 .3M97.1 80.2v-1.3l.4 .9 .4-.9v1.3M98.3 80.2l.4-1.3 .5 1.3M117.5 98.7h12.7v2.8M117.5 88.5h5.1M117.5 93.6h9.5M117.5 96.1h6.3v7.7h-6.3M117.5 86h5.1v7.6M117.5 91.1h5.1M117.5 83.4h5.1"/>
<path d="M127 90.4l-.8 1.3M127 90.4v10.8h-9.5M127 90.4l.8 1.3M149.2 99.3h-5.1v18M154.3 99.3h6.4M155.6 89.1h5.1M155.6 81.5h5.1M155.6 86.6h5.1M155.6 94.2h5.1M155.6 91.7h5.1M155.6 84.1h5.1M172 98.6v1.3h.6"/>
<path d="M180.8 91.6h.6l.1-.2v-.3l-.2-.1h-.5v1.2M196.2 96.8h17.2M196.2 99.3h13.3v10.2M196.2 81.5h5.1M196.2 86.6h5.1M205.7 96.8v7.6h-9.5M209.5 84.7h16.3M209.5 83.4v5.7h-13.3M212.1 96l1.3 .8M213.4 96.8l-1.3 .7M219.1 89.8h6.7M219.1 89.8l1.2 .7"/>
<path d="M220.3 89l-1.2 .8M221.6 82.2h4.2M225.8 92.3h-4.2v1.3h1.3l-1.3 1.3-1.3-1.3h1.3M225.8 87.2h-14.3v4.5h-15.3M243.5 87.9l.6-.1-.1-.3h-.3l-.2 .1 .1 .7h.4M10 110.3h2M30.5 101v4h1.2l-1.2 1.3-1.3-1.3h1.3M38.7 101v4h1.3l-1.3 1.3-1.2-1.3h1.2M51.4 107.6h5.1M51.4 105h5.1M51.4 102.5h5.1M71.7 107.2l.4-.3v1.2"/>
<path d="M71.7 108.1h.7M72 102.1l.3-.3v1.2M72 103h.7M72.4 104.7l.4-.4v1.3M72.4 105.6h.8M72.9 107l.5-.1 .2 .1 .1 .2-.1 .2-.7 .7h.8M73.1 101.8h.8l-.4 .5 .3 .1v.6h-.5l-.2-.1M74.3 104.3h-.6v.6l.1-.1 .5 .1v.6l-.2 .1-.4-.1M78.7 100.5h.8M117.5 106.3h5.1M117.5 108.8h5.1M122.6 108.8v1.3h1.2l-1.2 1.3-1.3-1.3h1.3"/>
<path d="M122.6 103.8v5M130.2 103.5v4.1h1.2l-1.2 1.2-1.3-1.2h1.3M144.1 119.4v4h1.3l-1.3 1.3-1.2-1.3h1.2M144.1 113.3h1.9M144.1 108.2h1.3M149.9 113.3h1.9M150.5 108.2h1.3M151.8 118.7v4.1h1.2l-1.2 1.3-1.3-1.3h1.3M159.1 113.1v1.1l.2 .2M160.7 101.8h-8.9v14.9M170.8 101.1v1.3h.6M196.2 106.9h13.3"/>
<path d="M196.2 101.8h9.5M196.2 109.5h13.3M209.5 109.5v1.2h1.3l-1.3 1.3-1.2-1.3h1.2M221 109.2v4.1h1.2l-1.2 1.2-1.3-1.2h1.3M221 101.8v5.4M221 101.8l-.8 1.3M221 101.8l.7 1.3M229.2 109.2v4.1h1.3l-1.3 1.2-1.2-1.2h1.2M229.2 101.8v5.4M229.2 101.8l-.7 1.3M229.2 101.8l.8 1.3M285 110.3h2"/>
<path d="M34.3 130.6l.3-.1 .1 .2v.6l-.3 .1-.3-.3zM35.4 130.5v.9M35.7 130.5l-.3 .3M40.6 139.3h3.8M40.6 134.2h3.8M40.6 136.8h3.8M44.4 139.2h1.3v.2h-1.3zM44.4 136.6h1.3v.3h-1.3zM44.4 134.1h1.3v.3h-1.3zM48.3 139.2h1.2v.2h-1.2zM48.3 136.6h1.2v.3h-1.2zM48.3 134.1h1.2v.3h-1.2z"/>
<path d="M49.5 139.3h3.8M49.5 134.2h3.8M49.5 136.8h3.8M85.7 133v3.8M85.7 133l-.7 1.2M85.7 133l.8 1.2M95.7 129.5v.1M95.7 129.9v.8M96.3 129.9h.3l.2 .1v.7h-.3l-.3-.2zM97.4 130l.2-.1h.3l.1 .8M97.4 129.9v.8M98.6 129.5v.1"/>
<path d="M98.6 129.9v.8M99.2 130l.2-.1h.3v.8M99.2 129.9v.8M100.9 129.9v1l-.3 .3-.3-.1M100.9 129.9h-.4l-.2 .2 .1 .6h.5M116.4 139.3h7.4M121.9 133v13.9h-5.5M121.9 133l-.7 1.2M121.9 133l.8 1.2M126.7 129.9h.3l.3 .2-.1 .6h-.4l-.1-.1zM127.8 129.9v.8M128.2 129.9l-.4 .2"/>
<path d="M129 129.9h-.3l-.2 .2 .1 .1 .4 .2v.3h-.5M139.3 139.3h7.4M144.8 133v13.9h-5.5M144.8 133l-.8 1.2M144.8 133l.7 1.2M172.5 129.9h.5M172.7 129.5v1.1l.3 .1M173.4 129.9v.8M173.8 129.9h-.3l-.1 .2M174.2 130l.2-.1h.3l.1 .2-.1 .6h-.3l-.2-.1zM175.4 129.5v1.1l.1 .1M184.1 133.6h5.1"/>
<path d="M184.1 133.6l1.3 .8M185.4 132.8l-1.3 .8M194.3 138.7v16.5h1.3l-1.3 1.3-1.3-1.3h1.3M199.4 133.6h22M204.7 136.4h4.6v.5h-4.6zM205.2 135.1h1M205.7 134.6v1M207 138.4v4.1h1.3l-1.3 1.3-1.3-1.3h1.3M207 133.6v2.8M212.7 133.6v7.6h4.5M221.4 136.1h-4.2v12.1l-1.9 1.9M40.6 141.9h3.8"/>
<path d="M40.6 144.4h3.8M40.6 146.9h3.8M40.6 149.5h3.8M42.7 157.9l.3-.1 .3 .3-.1 .5h-.5M42.7 157.8v1.3M43.8 157.9l.4-.1 .2 .3-.1 .5h-.5M43.8 157.8v1.3M44.4 146.8h1.3v.3h-1.3zM44.4 149.3h1.3v.3h-1.3zM44.4 151.9h1.3v.2h-1.3zM44.4 144.3h1.3v.2h-1.3zM44.4 141.7h1.3v.3h-1.3z"/>
<path d="M44.4 152h-3.8v1.3h1.3l-1.3 1.3-1.2-1.3h1.2M45 157.4v1.1l.1 .2M45.5 157.8l.3 .9M46.1 157.8l-.4 1.2-.2 .1M48.3 146.8h1.2v.3h-1.2zM48.3 149.3h1.2v.3h-1.2zM48.3 151.9h1.2v.2h-1.2zM48.3 144.3h1.2v.2h-1.2zM48.3 141.7h1.2v.3h-1.2zM49.5 141.9h3.8M49.5 144.4h3.8M49.5 146.9h3.8"/>
<path d="M49.5 149.5h3.8M49.5 152h6.4M54.6 151.3l1.3 .7M55.9 152l-1.3 .8M72.6 145.7h4.2v1.2h1.3l-1.3 1.3-1.2-1.3h1.2M72.6 143.1h19.5M85.7 141.9v10.1h1.3l-1.3 1.3-1.2-1.3h1.2M97.2 143.1h3.1v2.8M100.3 147.9v4.1h1.3l-1.3 1.3-1.2-1.3h1.2M116.4 149.5h6.2v1.2h1.2l-1.2 1.3-1.3-1.3h1.3M116.4 141.9h12.5M116.4 144.4h12.5"/>
<path d="M139.3 149.5h6.1v1.2h1.3l-1.3 1.3-1.3-1.3h1.3M139.3 141.9h12.5M139.3 144.4h12.5M169.5 148.8h1.3M175.9 148.8h7M182.9 149.5l1.9 1.9v3.8h1.3l-1.3 1.3-1.3-1.3h1.3M194.3 143.8h-9.5v2.5l-1.9 1.9M203.2 150.7h-1.3v5.1M208.3 150.7h7M215.3 151.4l1.9 1.9v3.8h1.2l-1.2 1.3-1.3-1.3h1.3M10 160.2h2M25.6 169.2h6.1"/>
<path d="M25.6 171.7h23.9M33 171.7v16.5h12.1v-8.2M45.1 171.7v-8.3h-13.4v16.6h17.8M47.2 175.1h4.6v.5h-4.6zM47.8 173.9h1M48.3 173.3v1.1M49.5 177.2v5.9h1.3l-1.3 1.3-1.2-1.3h1.2M49.5 167.9l-.7 1.3M49.5 167.9v7.2M49.5 167.9l.8 1.3M64.4 174.2h11.2v14h1.2l-1.2 1.3-1.3-1.3h1.3M64.4 169.2h11.2v2.5"/>
<path d="M64.4 171.7h33.4M64.4 176.8h11.2M83.2 164.1l-.8 1.2M83.2 164.1v18M83.2 164.1l.7 1.2M95.2 176.8h2.6M113 171.7h12.7a.63 .63 0 0 1 .7-.6 .63 .63 0 0 1 .6 .6 .63 .63 0 0 1 .6-.6 .63 .63 0 0 1 .7 .6 .63 .63 0 0 1 .6-.6 .63 .63 0 0 1 .6 .6 .63 .63 0 0 1 .7-.6 .63 .63 0 0 1 .6 .6h18.4M113 176.8h5.4M120.4 176.8h2.8M123.2 171.7v14h1.3l-1.3 1.2-1.3-1.2h1.3M139.3 174.5h4.6v.5h-4.6zM139.8 173.2h1"/>
<path d="M140.3 172.7v1M141.6 176.5v7.3h1.3l-1.3 1.2-1.3-1.2h1.3M141.6 171.7v2.8M149.2 169.2v3.8M149.2 178v5.1M149.2 169.2l-.7 1.2M149.2 169.2l.8 1.2M170.3 164.6l.5-.1v-.3h-.4l-.1 .2v.6h.5M171.8 164.2h-.3l-.2 .2 .1 .1 .4 .2v.3h-.5M177 166.3h108v32h-108zM285 160.2h2M60 198.3v1.9"/>
<path d="M83.2 184.1v4.1h1.3l-1.3 1.3-1.3-1.3h1.3M105.4 184.4v3.8h1.3l-1.3 1.3-1.3-1.3h1.3M110 198.3v1.9M149.2 188.2v2.5h1.3l-1.3 1.3-1.2-1.3h1.2M149.2 180.6h-3.2v8.2h-27.3v-6.9h-5.7M160 198.3v1.9M177 194.8h108M177 191.8h108M177 187.8h108M177 181.8h108M186.5 192.5l-.4 1h1M186.8 193v1"/>
<path d="M187.6 182.3l-1.3 2M197 191.8v3M201.9 186.5v.1M203.1 185.7a.37 .37 0 0 0-.6 .1l.1 .2 .5 .2 .1 .1-.2 .3-.5-.1M204.5 185.7l-.5-.1-.2 .3v.6l.2 .1 .5-.1M205.1 185.7h.1a.37 .37 0 0 1 .6 .1v.8M205.1 185.1v1.5M210 198.3v1.9M231.6 196l.2-.2 .4 .1v.9M231.6 195.8v1M232.7 195.8h.6M232.9 195.3v1.3l.4 .2"/>
<path d="M233.8 195.8l.1 .9 .3 .1 .2-.1M234.4 195.8v1M235.1 195.8l.4-.5v1.5M235.1 196.8h.8M236.8 196l-.2-.2v-.3a.48 .48 0 0 1 .6-.1l.2 .2-.2 .3-.5 .1-.2 .3 .1 .4 .2 .1h.3l.3-.3v-.2l-.3-.3M238 196.7v.1M238.8 195.5l.3-.2a.94 .94 0 0 1 0 1.5 .82 .82 0 0 1-.3-1.3zM240.4 195.2l-.3 1.1h.9M240.8 195.8v1M241.6 196.7v.1M242.2 195.8l.4-.5v1.5M242.2 196.8h.9"/>
<path d="M260 198.3v1.9M261 191.8v6.5M269.8 195.2l-1.2 2M270.3 195.8l.4-.5v1.5M270.3 196.8h.8"/>
<circle cx="204.6" cy="28.2" r=".76"/>
<circle cx="204.6" cy="33.3" r=".76"/>
<circle cx="204.6" cy="30.7" r=".76"/>
<circle cx="48.1" cy="59.3" r=".76"/>
<circle cx="48.1" cy="64.4" r=".76"/>
<circle cx="48.1" cy="61.8" r=".76"/>
</g>
<g fill="none" stroke="#000" stroke-width=".25">
<path d="M160.7 19.3h35.5v94h-35.5zM56.5 21.2h61v90.2h-61zM220 26.3h2v5.1h-2zM230.5 25h15.2v10.2h-15.2zM225.4 56.1l2.6 1.3-2.6 1.3zM228 56.1v2.6M231.8 56.4h5.1v2h-5.1zM208.5 78.4h2.1v5h-2.1zM225.4 63.7l2.6 1.3-2.6 1.3zM225.4 71.4l2.6 1.2-2.6 1.3zM228 63.7v2.6M228 71.4v2.5"/>
<path d="M231.8 71.6h5.1v2.1h-5.1zM231.8 64h5.1v2h-5.1zM149.2 98.3h5.1v2h-5.1zM145.4 107.2h5.1v2h-5.1zM44.4 133h5.1v20.3h-5.1zM84.7 136.8h2v5.1h-2zM189.2 131.7h10.2v7h-10.2zM211.5 136.1h2.5M212.7 136.1l1.3 2.6h-2.5zM84.5 145.7h2.5v.5M85.7 145.7l1.3 2.5h-2.5zM92.1 142.1h5.1v2h-5.1z"/>
<path d="M170.8 147.8h5.1v2.1h-5.1zM193 148.8h2.6v.5M194.3 148.8l1.3 2.6h-2.6zM203.2 149.7h5.1v2.1h-5.1zM40 180l2.5-1.3v2.5zM40 170.4l2.5 1.3-2.5 1.3zM40 162.2l2.5 1.2-2.5 1.3zM40 178.7v2.5M42.5 162.2v2.5M42.5 170.4v2.6M97.8 169.2h15.2v15.2h-15.2zM123.2 179.3l1.3 2.6h-2.6z"/>
<path d="M123.8 178.7h.7v.6h-2.6v.7h.7M148.2 173h2v5h-2zM40 188.2l2.5-1.3v2.6zM40 186.9v2.6M148.2 183.1h2v5.1h-2z"/>
<circle cx="183.5" cy="148.8" r="2.82"/>
<circle cx="215.9" cy="150.7" r="2.82"/>
</g>
<g fill="#000" stroke="#000" stroke-width=".18">
<path d="M225.8 82h.9v.3h-.9zM225.8 84.6h.9v.2h-.9zM225.8 87.1h.9v.3h-.9zM225.8 89.7h.9v.2h-.9zM225.8 92.2h.9v.3h-.9zM115.6 139.2h.8v.2h-.8zM138.4 139.2h.9v.2h-.9zM204.7 137.9h4.6v.5h-4.6zM221.4 136h.8v.3h-.8zM221.4 133.5h.8v.2h-.8zM71.8 143h.8v.3h-.8zM71.8 145.5h.8v.3h-.8z"/>
<path d="M115.6 141.7h.8v.3h-.8zM115.6 144.3h.8v.2h-.8zM115.6 146.8h.8v.3h-.8zM115.6 149.3h.8v.3h-.8zM138.4 141.7h.9v.3h-.9zM138.4 144.3h.9v.2h-.9zM138.4 146.8h.9v.3h-.9zM138.4 149.3h.9v.3h-.9zM183.5 150.6l.5-.5 .5 1zM215.9 152.5l.5-.5 .5 1zM24.8 169h.8v.3h-.8zM24.8 171.6h.8v.2h-.8z"/>
<path d="M47.2 176.7h4.6v.5h-4.6zM63.5 169h.9v.3h-.9zM63.5 171.6h.9v.2h-.9zM63.5 174.1h.9v.3h-.9zM63.5 176.7h.9v.2h-.9zM139.3 176h4.6v.5h-4.6z"/>
</g>
<g fill="none" stroke="#000" stroke-width=".51">
<path d="M213.9 33.1h4M213.9 34.7h4M36.7 77.6h4.1M36.7 79.1h4.1M28.4 99.2h4.1M36.7 99.2h4.1M28.4 100.7h4.1M36.7 100.7h4.1M128.1 101.7h4.1M128.1 103.2h4.1M142.1 117.6h4.1M142.1 119.1h4.1"/>
<path d="M146 112v2.5M149.7 117h4.1M149.7 118.5h4.1M149.9 112v2.5M218.9 107.4h4.1M218.9 109h4.1M227.2 107.4h4.1M227.2 109h4.1M98.3 146.2h4.1M98.3 147.7h4.1M182.9 146.9v3.8M215.3 148.8v3.8"/>
<path d="M118.6 174.7v4.1M120.1 174.7v4.1M81.2 182.4h4M81.2 183.9h4"/>
</g>
<path d="M146.8 110.7h2.3v5.1h-2.3z" fill="none" stroke="#000" stroke-width=".3"/>
<g fill="none" stroke="#000" stroke-width="1.3">
<circle cx="160.7" cy="172.3" r="1.27"/>
<circle cx="160.7" cy="177.4" r="1.27"/>
<circle cx="168.9" cy="177.4" r="1.27"/>
<circle cx="168.9" cy="172.3" r="1.27"/>
</g>
<g fill="none" stroke="#000" stroke-width=".18" stroke-dasharray=".4 .4">
<path d="M22.2 13.6v113.6M259.1 13.6h-236.9M22.2 128.5h43.8M22.2 127.2h236.9M66 128.5v26.7M67.3 128.5h42.6M109.9 128.5v26.7M111.1 128.5v26.7M155.6 128.5h-44.5M156.8 128.5h69.3M226.1 128.5v33M259.1 127.2v-113.6"/>
<path d="M22.2 156.5h133.4M22.2 155.2v-26.7M66 155.2h-43.8M67.3 155.2v-26.7M109.9 155.2h-42.6M111.1 155.2h44.5M123.2 141.2h2.5M123.8 140.6l-.6 .6M125.1 143.8h2.5M127 143.1l.6 .7M146 141.2h2.6M146.7 140.6l-.7 .6"/>
<path d="M148 143.8h2.5M149.9 143.1l.6 .7M155.6 156.5v38.1M155.6 155.2v-26.7M156.8 162.8h18.5M156.8 161.5v-33M175.3 162.8v26.7M226.1 161.5h-69.3M22.2 194.6v-38.1M155.6 194.6h-133.4M156.8 189.5v-26.7M175.3 189.5h-18.5"/>
</g>
<path d="M219.4 189.7l-.6-.1-.3 .3v.6l.2 .3 .1 .1 .6-.1M219.4 188.9v2M221.9 188.9a1.06 1.06 0 0 1 1.1 .6 1.06 1.06 0 0 1-.3 1.3l-.8 .1zM223.8 189.5l.6-.6v2M223.8 190.9h1.2" fill="none" stroke="#000" stroke-width=".41"/>
<g fill="#000" stroke="#000" stroke-width=".25">
<circle cx="221" cy="22.5" r=".51"/>
<circle cx="228" cy="27.6" r=".51"/>
<circle cx="228" cy="22.5" r=".51"/>
<circle cx="238.1" cy="22.5" r=".51"/>
<circle cx="122.6" cy="93.6" r=".51"/>
<circle cx="122.6" cy="88.5" r=".51"/>
<circle cx="122.6" cy="91.1" r=".51"/>
<circle cx="127" cy="93.6" r=".51"/>
<circle cx="205.7" cy="96.8" r=".51"/>
<circle cx="209.6" cy="84.7" r=".51"/>
<circle cx="122.6" cy="108.8" r=".51"/>
<circle cx="122.6" cy="103.8" r=".51"/>
<circle cx="122.6" cy="106.3" r=".51"/>
<circle cx="144.1" cy="108.2" r=".51"/>
<circle cx="144.1" cy="113.3" r=".51"/>
<circle cx="151.8" cy="113.3" r=".51"/>
<circle cx="151.8" cy="108.2" r=".51"/>
<circle cx="205.7" cy="101.8" r=".51"/>
<circle cx="209.6" cy="109.5" r=".51"/>
<circle cx="209.6" cy="106.9" r=".51"/>
<circle cx="207" cy="133.6" r=".51"/>
<circle cx="212.7" cy="133.6" r=".51"/>
<circle cx="85.7" cy="143.1" r=".51"/>
<circle cx="194.3" cy="143.8" r=".51"/>
<circle cx="217.2" cy="141.2" r=".51"/>
<circle cx="31.8" cy="169.2" r=".51"/>
<circle cx="33" cy="171.7" r=".51"/>
<circle cx="45.1" cy="171.7" r=".51"/>
<circle cx="45.1" cy="180" r=".51"/>
<circle cx="49.5" cy="180" r=".51"/>
<circle cx="49.5" cy="171.7" r=".51"/>
<circle cx="75.6" cy="176.8" r=".51"/>
<circle cx="75.6" cy="171.7" r=".51"/>
<circle cx="83.2" cy="171.7" r=".51"/>
<circle cx="123.2" cy="176.8" r=".51"/>
<circle cx="123.2" cy="171.7" r=".51"/>
<circle cx="141.6" cy="171.7" r=".51"/>
<circle cx="149.2" cy="171.7" r=".51"/>
<circle cx="149.2" cy="180.6" r=".51"/>
</g>
<use href="#words"/>
</svg>
